VERSION 5.7 ;
  NOWIREEXTENSIONATPIN ON ;
  DIVIDERCHAR "/" ;
  BUSBITCHARS "[]" ;
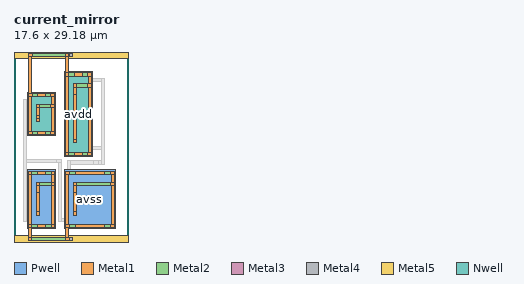
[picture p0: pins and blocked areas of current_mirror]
MACRO current_mirror
  CLASS BLOCK ;
  FOREIGN current_mirror ;
  ORIGIN 0.000 0.000 ;
  SIZE 17.600 BY 29.180 ;
  PIN avss
    USE GROUND ;
    ANTENNADIFFAREA 24.695999 ;
    PORT
      LAYER Pwell ;
        RECT 2.000 2.000 6.440 11.090 ;
        RECT 7.740 2.000 15.600 11.090 ;
      LAYER Metal1 ;
        RECT 2.230 10.380 2.730 10.880 ;
        RECT 3.570 10.380 4.870 10.880 ;
        RECT 5.710 10.380 6.210 10.880 ;
        RECT 2.230 2.710 2.690 10.380 ;
        RECT 5.750 9.190 6.210 10.380 ;
        RECT 3.400 8.690 3.900 9.190 ;
        RECT 5.710 8.690 6.210 9.190 ;
        RECT 3.420 7.590 3.880 8.690 ;
        RECT 3.400 4.690 3.900 7.590 ;
        RECT 3.420 4.140 3.880 4.690 ;
        RECT 5.750 2.710 6.210 8.690 ;
        RECT 2.230 2.210 2.730 2.710 ;
        RECT 3.570 2.210 4.870 2.710 ;
        RECT 5.710 2.210 6.210 2.710 ;
        RECT 7.970 10.380 8.470 10.880 ;
        RECT 9.420 10.380 13.920 10.880 ;
        RECT 14.870 10.380 15.370 10.880 ;
        RECT 7.970 2.710 8.430 10.380 ;
        RECT 14.910 9.190 15.370 10.380 ;
        RECT 9.140 8.690 9.640 9.190 ;
        RECT 14.870 8.690 15.370 9.190 ;
        RECT 9.160 7.590 9.620 8.690 ;
        RECT 9.140 4.690 9.640 7.590 ;
        RECT 9.160 4.140 9.620 4.690 ;
        RECT 14.910 2.710 15.370 8.690 ;
        RECT 7.970 2.210 8.470 2.710 ;
        RECT 9.420 2.210 13.920 2.710 ;
        RECT 14.870 2.210 15.370 2.710 ;
        RECT 2.230 0.750 2.690 2.210 ;
        RECT 7.970 0.750 8.430 2.210 ;
        RECT 2.230 0.250 2.730 0.750 ;
        RECT 7.970 0.250 8.470 0.750 ;
      LAYER Metal2 ;
        RECT 2.230 10.380 6.210 10.880 ;
        RECT 7.970 10.380 15.370 10.880 ;
        RECT 3.400 8.690 6.210 9.190 ;
        RECT 9.140 8.690 15.370 9.190 ;
        RECT 3.400 4.140 3.900 8.140 ;
        RECT 9.140 4.140 9.640 8.140 ;
        RECT 2.230 2.210 6.210 2.710 ;
        RECT 7.970 2.210 15.370 2.710 ;
        RECT 2.230 0.250 9.050 0.750 ;
      LAYER Metal3 ;
        RECT 8.550 0.250 9.050 0.750 ;
      LAYER Metal4 ;
        RECT 8.550 0.250 9.050 0.750 ;
      LAYER Metal5 ;
        RECT 0.000 0.000 17.600 1.000 ;
    END
  END avss
  PIN avdd
    USE POWER ;
    ANTENNADIFFAREA 23.630400 ;
    PORT
      LAYER Nwell ;
        RECT 2.040 16.290 6.400 22.980 ;
        RECT 7.700 13.090 12.060 26.180 ;
      LAYER Metal1 ;
        RECT 2.270 28.430 2.770 28.930 ;
        RECT 7.930 28.430 8.430 28.930 ;
        RECT 2.270 22.770 2.730 28.430 ;
        RECT 7.930 25.970 8.390 28.430 ;
        RECT 7.930 25.470 8.430 25.970 ;
        RECT 9.230 25.470 10.530 25.970 ;
        RECT 11.330 25.470 11.830 25.970 ;
        RECT 2.270 22.270 2.770 22.770 ;
        RECT 3.570 22.270 4.870 22.770 ;
        RECT 5.670 22.270 6.170 22.770 ;
        RECT 2.270 17.000 2.730 22.270 ;
        RECT 5.710 21.080 6.170 22.270 ;
        RECT 3.440 20.580 3.940 21.080 ;
        RECT 5.670 20.580 6.170 21.080 ;
        RECT 3.460 19.480 3.920 20.580 ;
        RECT 3.440 18.980 3.940 19.480 ;
        RECT 3.460 18.430 3.920 18.980 ;
        RECT 5.710 17.000 6.170 20.580 ;
        RECT 2.270 16.500 2.770 17.000 ;
        RECT 3.570 16.500 4.870 17.000 ;
        RECT 5.670 16.500 6.170 17.000 ;
        RECT 7.930 13.800 8.390 25.470 ;
        RECT 11.370 24.280 11.830 25.470 ;
        RECT 9.100 23.780 9.600 24.280 ;
        RECT 11.330 23.780 11.830 24.280 ;
        RECT 9.120 22.680 9.580 23.780 ;
        RECT 9.100 15.780 9.600 22.680 ;
        RECT 9.120 15.230 9.580 15.780 ;
        RECT 11.370 13.800 11.830 23.780 ;
        RECT 7.930 13.300 8.430 13.800 ;
        RECT 9.230 13.300 10.530 13.800 ;
        RECT 11.330 13.300 11.830 13.800 ;
      LAYER Metal2 ;
        RECT 2.270 28.430 9.050 28.930 ;
        RECT 7.930 25.470 11.830 25.970 ;
        RECT 9.100 23.780 11.830 24.280 ;
        RECT 2.270 22.270 6.170 22.770 ;
        RECT 3.440 20.580 6.170 21.080 ;
        RECT 3.440 18.430 3.940 20.030 ;
        RECT 2.270 16.500 6.170 17.000 ;
        RECT 9.100 15.230 9.600 23.230 ;
        RECT 7.930 13.300 11.830 13.800 ;
      LAYER Metal3 ;
        RECT 8.550 28.430 9.050 28.930 ;
      LAYER Metal4 ;
        RECT 8.550 28.430 9.050 28.930 ;
      LAYER Metal5 ;
        RECT 0.000 28.180 17.600 29.180 ;
    END
  END avdd
  OBS
      LAYER Metal1 ;
        RECT 10.160 24.580 10.660 25.080 ;
        RECT 10.180 22.680 10.640 24.580 ;
        RECT 4.500 21.380 5.000 21.880 ;
        RECT 4.520 19.480 4.980 21.380 ;
        RECT 4.500 18.980 5.000 19.480 ;
        RECT 4.520 18.430 4.980 18.980 ;
        RECT 3.970 17.390 4.470 17.890 ;
        RECT 10.160 15.780 10.660 22.680 ;
        RECT 10.180 15.230 10.640 15.780 ;
        RECT 9.630 14.190 10.130 14.690 ;
        RECT 4.540 9.490 5.040 9.990 ;
        RECT 13.700 9.490 14.200 9.990 ;
        RECT 4.560 7.590 5.020 9.490 ;
        RECT 13.720 7.590 14.180 9.490 ;
        RECT 4.540 4.690 5.040 7.590 ;
        RECT 13.700 4.690 14.200 7.590 ;
        RECT 4.560 4.140 5.020 4.690 ;
        RECT 13.720 4.140 14.180 4.690 ;
        RECT 3.970 3.100 4.470 3.600 ;
        RECT 10.220 3.100 10.720 3.600 ;
        RECT 11.020 3.100 11.520 3.600 ;
        RECT 11.820 3.100 12.320 3.600 ;
        RECT 12.620 3.100 13.120 3.600 ;
      LAYER Metal2 ;
        RECT 9.100 24.580 13.930 25.080 ;
        RECT 1.470 21.380 5.000 21.880 ;
        RECT 4.500 18.430 5.000 20.030 ;
        RECT 1.470 17.390 4.470 17.890 ;
        RECT 10.160 15.230 10.660 23.230 ;
        RECT 9.630 14.190 13.930 14.690 ;
        RECT 1.470 12.140 7.270 12.640 ;
        RECT 8.140 11.940 13.930 12.440 ;
        RECT 1.470 9.490 5.040 9.990 ;
        RECT 8.140 9.490 14.200 9.990 ;
        RECT 4.540 4.140 5.040 8.140 ;
        RECT 13.700 4.140 14.200 8.140 ;
        RECT 1.470 3.100 4.470 3.600 ;
        RECT 6.770 3.100 13.670 3.600 ;
      LAYER Metal3 ;
        RECT 1.470 3.100 1.970 21.880 ;
        RECT 6.520 12.140 7.270 12.640 ;
        RECT 6.770 3.100 7.270 12.140 ;
        RECT 8.140 9.490 8.640 12.440 ;
        RECT 12.180 11.940 12.930 12.440 ;
        RECT 13.430 11.940 13.930 25.080 ;
  END
END current_mirror
END LIBRARY

